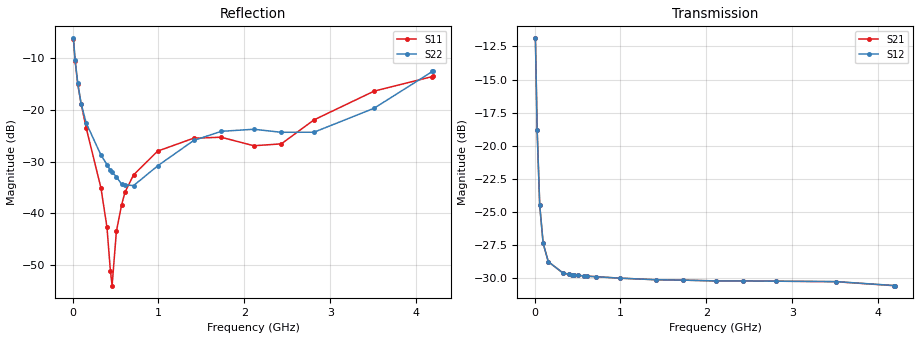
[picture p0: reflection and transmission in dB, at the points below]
! Integrated Device Technology
! Corporate Headquarters
! 6024 Silver Creek Valley Road
! San Jose, CA 95138  USA
! Phone:  1-408-284-8200
! Toll Free:  1-800-223-1366
! Webpage:  http://www.idt.com/
! Timing and RF Division
! 515 Groton Road, Suite 102
! Westford, MA 01886-6024
! Device:  F1950
! Description: 7-bit 0.25 dB Digital Step Attenuator
! Frequency:  150.0 -  4000.00 MHz
! Package:  4x4 mm Thin QFN Plastic Package: 24 pin
! Ports:  2 RF, 12 DC
!  Pin  1  = D0
!  Pin  2  = VDD
!  Pin  3  = Vmode
!  Pin  4  = GND
!  Pin  5  = RF1  =  Port 1
!  Pin  6  = GND
!  Pin  7  = GND
!  Pin  8  = GND
!  Pin  9  = GND
!  Pin 10  = GND
!  Pin 11  = GND
!  Pin 12  = GND
!  Pin 13  = GND
!  Pin 14  = RF2  =  Port 2
!  Pin 15  = GND
!  Pin 16  = LE
!  Pin 17  = CLK
!  Pin 18  = DATE
!  Pin 19  = D6
!  Pin 20  = D5
!  Pin 21  = D4
!  Pin 22  = D3
!  Pin 23  = D2
!  Pin 24  = D1
! State:  116
! Atten State:  29.00 dB
! Voltage:  +5.00 Volts
! Current:  Not Measured mA
! Data:  The device was measured on a the F195X evaluation board which has
!  individual transmission lines to the RF pins.  Data was collected
!  using a calibrated network analyzer.  The evaluation board was
!  de-embedded using a TRL calibration technique.
!  The reference plane is the edge of the package pin.
! Misc:  Board 2019
!  Action Tracker AT0250
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# GHz S dB R 50
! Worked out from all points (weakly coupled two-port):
!   420 points, 10 MHz to 4.2 GHz, reference 50 ohm
!   highest |S21| = -11.89 dB at 10 MHz (marker M1); lowest = -30.6 dB at 4.19 GHz (marker M2)
!   lowest |S11| = -54.0 dB at 460 MHz (marker M3), VSWR 1.00, Z = 49.8 - j0.0404 ohm
!   |S11| at or under -10 dB: 26.8 MHz to end of sweep
!   |S22| runs from -35.0 to -6.2 dB; largest |S21 - S12| = 7.4e-05
!   S11 on the Smith chart (normalised r, x): 10 MHz: 1.99, -1.17; 30 MHz: 1.27, -0.64; 60 MHz: 1.11, -0.36; 400 MHz: 1.00, -0.01; 4.2 GHz: 0.69, +0.17
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0.01  -6.42 -28.5  -11.89 -40.5  -11.89 -40.5  -6.21 -29.4
0.03  -10.62 -51.1  -18.80 -61.7  -18.80 -61.7  -10.48 -53.0
0.06  -15.04 -63.9  -24.49 -55.4  -24.49 -55.4  -14.79 -65.7
0.1  -18.91 -70.7  -27.36 -41.9  -27.36 -41.9  -18.87 -71.3
0.16  -23.60 -72.7  -28.75 -29.7  -28.75 -29.7  -22.61 -76.5
0.33  -35.07 -72.8  -29.60 -17.7  -29.60 -17.7  -28.73 -85.7
0.4  -42.64 -77.9  -29.70 -16.0  -29.69 -16.0  -30.57 -89.0
0.44  -51.04 -108.5  -29.74 -15.3  -29.73 -15.3  -31.68 -93.8
0.46  -53.96 -168.3  -29.75 -15.0  -29.75 -15.0  -32.08 -97.3
0.51  -43.47 141.6  -29.79 -14.5  -29.78 -14.5  -32.90 -103.2
0.57  -38.41 135.7  -29.82 -14.1  -29.82 -14.1  -34.38 -114.2
0.61  -35.91 136.9  -29.84 -13.9  -29.84 -13.9  -34.48 -122.5
0.71  -32.57 138.0  -29.88 -13.7  -29.88 -13.7  -34.64 -142.0
0.99  -27.98 146.9  -29.99 -14.4  -29.99 -14.4  -30.83 178.9
1.41  -25.48 162.1  -30.11 -16.3  -30.11 -16.3  -25.92 159.9
1.73  -25.30 167.2  -30.14 -18.0  -30.14 -18.0  -24.16 151.6
2.11  -26.94 156.4  -30.20 -20.9  -30.20 -20.9  -23.76 141.7
2.43  -26.58 125.1  -30.20 -22.8  -30.20 -22.8  -24.34 130.8
2.81  -21.95 104.8  -30.22 -25.9  -30.22 -25.9  -24.33 115.4
3.51  -16.40 116.9  -30.26 -30.9  -30.25 -31.0  -19.70 112.8
4.19  -13.58 144.8  -30.56 -33.5  -30.55 -33.6  -12.59 127.0
4.2  -13.50 145.1  -30.56 -33.5  -30.55 -33.6  -12.47 126.9
